VERSION 5.7 ;
  NOWIREEXTENSIONATPIN ON ;
  DIVIDERCHAR "/" ;
  BUSBITCHARS "[]" ;
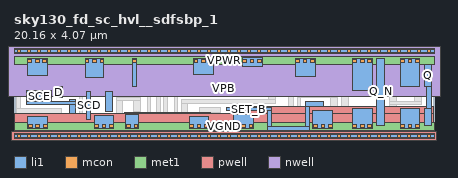
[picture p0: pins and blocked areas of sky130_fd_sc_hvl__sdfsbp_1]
MACRO sky130_fd_sc_hvl__sdfsbp_1
  CLASS BLOCK ;
  FOREIGN sky130_fd_sc_hvl__sdfsbp_1 ;
  ORIGIN 0.000 0.000 ;
  SIZE 20.160 BY 4.070 ;
  PIN CLK
    ANTENNAGATEAREA 0.585000 ;
    PORT
      LAYER li1 ;
        RECT 4.380 1.180 4.710 2.150 ;
    END
  END CLK
  PIN D
    ANTENNAGATEAREA 0.420000 ;
    PORT
      LAYER li1 ;
        RECT 1.975 1.845 2.305 2.355 ;
    END
  END D
  PIN SCD
    ANTENNAGATEAREA 0.420000 ;
    PORT
      LAYER li1 ;
        RECT 3.485 0.810 3.690 2.150 ;
    END
  END SCD
  PIN SCE
    ANTENNAGATEAREA 0.840000 ;
    PORT
      LAYER li1 ;
        RECT 0.605 1.665 1.795 2.165 ;
        RECT 2.680 1.665 2.955 1.765 ;
        RECT 0.605 1.495 2.955 1.665 ;
        RECT 2.680 1.095 2.955 1.495 ;
    END
  END SCE
  PIN SET_B
    ANTENNAGATEAREA 0.840000 ;
    PORT
      LAYER li1 ;
        RECT 14.000 1.425 14.845 1.645 ;
        RECT 10.205 1.210 12.355 1.380 ;
        RECT 12.185 0.435 12.355 1.210 ;
        RECT 14.000 0.435 14.170 1.425 ;
        RECT 12.185 0.265 14.170 0.435 ;
    END
  END SET_B
  PIN VGND
    USE GROUND ;
    PORT
      LAYER li1 ;
        RECT 0.665 0.365 1.615 0.915 ;
        RECT 3.870 0.365 4.760 0.995 ;
        RECT 5.370 0.365 5.960 1.020 ;
        RECT 8.410 0.365 9.360 0.960 ;
        RECT 10.545 0.365 11.495 1.030 ;
        RECT 14.350 0.365 15.300 1.245 ;
        RECT 16.240 0.365 17.190 1.325 ;
        RECT 18.535 0.365 19.485 1.325 ;
      LAYER mcon ;
        RECT 0.695 0.395 0.865 0.565 ;
        RECT 1.055 0.395 1.225 0.565 ;
        RECT 1.415 0.395 1.585 0.565 ;
        RECT 3.870 0.395 4.040 0.565 ;
        RECT 4.230 0.395 4.400 0.565 ;
        RECT 4.590 0.395 4.760 0.565 ;
        RECT 5.400 0.395 5.570 0.565 ;
        RECT 5.760 0.395 5.930 0.565 ;
        RECT 8.440 0.395 8.610 0.565 ;
        RECT 8.800 0.395 8.970 0.565 ;
        RECT 9.160 0.395 9.330 0.565 ;
        RECT 10.575 0.395 10.745 0.565 ;
        RECT 10.935 0.395 11.105 0.565 ;
        RECT 11.295 0.395 11.465 0.565 ;
        RECT 14.380 0.395 14.550 0.565 ;
        RECT 14.740 0.395 14.910 0.565 ;
        RECT 15.100 0.395 15.270 0.565 ;
        RECT 16.270 0.395 16.440 0.565 ;
        RECT 16.630 0.395 16.800 0.565 ;
        RECT 16.990 0.395 17.160 0.565 ;
        RECT 18.565 0.395 18.735 0.565 ;
        RECT 18.925 0.395 19.095 0.565 ;
        RECT 19.285 0.395 19.455 0.565 ;
      LAYER met1 ;
        RECT 0.000 0.255 20.160 0.625 ;
    END
  END VGND
  PIN VNB
    ANTENNADIFFAREA 3.427200 ;
    PORT
      LAYER pwell ;
        RECT 6.650 1.130 9.450 1.150 ;
        RECT 5.320 1.085 9.450 1.130 ;
        RECT 11.075 1.085 20.140 1.415 ;
        RECT 0.045 0.215 20.140 1.085 ;
        RECT -0.130 -0.215 20.290 0.215 ;
      LAYER li1 ;
        RECT 0.000 -0.085 20.160 0.085 ;
      LAYER mcon ;
        RECT 0.155 -0.085 0.325 0.085 ;
        RECT 0.635 -0.085 0.805 0.085 ;
        RECT 1.115 -0.085 1.285 0.085 ;
        RECT 1.595 -0.085 1.765 0.085 ;
        RECT 2.075 -0.085 2.245 0.085 ;
        RECT 2.555 -0.085 2.725 0.085 ;
        RECT 3.035 -0.085 3.205 0.085 ;
        RECT 3.515 -0.085 3.685 0.085 ;
        RECT 3.995 -0.085 4.165 0.085 ;
        RECT 4.475 -0.085 4.645 0.085 ;
        RECT 4.955 -0.085 5.125 0.085 ;
        RECT 5.435 -0.085 5.605 0.085 ;
        RECT 5.915 -0.085 6.085 0.085 ;
        RECT 6.395 -0.085 6.565 0.085 ;
        RECT 6.875 -0.085 7.045 0.085 ;
        RECT 7.355 -0.085 7.525 0.085 ;
        RECT 7.835 -0.085 8.005 0.085 ;
        RECT 8.315 -0.085 8.485 0.085 ;
        RECT 8.795 -0.085 8.965 0.085 ;
        RECT 9.275 -0.085 9.445 0.085 ;
        RECT 9.755 -0.085 9.925 0.085 ;
        RECT 10.235 -0.085 10.405 0.085 ;
        RECT 10.715 -0.085 10.885 0.085 ;
        RECT 11.195 -0.085 11.365 0.085 ;
        RECT 11.675 -0.085 11.845 0.085 ;
        RECT 12.155 -0.085 12.325 0.085 ;
        RECT 12.635 -0.085 12.805 0.085 ;
        RECT 13.115 -0.085 13.285 0.085 ;
        RECT 13.595 -0.085 13.765 0.085 ;
        RECT 14.075 -0.085 14.245 0.085 ;
        RECT 14.555 -0.085 14.725 0.085 ;
        RECT 15.035 -0.085 15.205 0.085 ;
        RECT 15.515 -0.085 15.685 0.085 ;
        RECT 15.995 -0.085 16.165 0.085 ;
        RECT 16.475 -0.085 16.645 0.085 ;
        RECT 16.955 -0.085 17.125 0.085 ;
        RECT 17.435 -0.085 17.605 0.085 ;
        RECT 17.915 -0.085 18.085 0.085 ;
        RECT 18.395 -0.085 18.565 0.085 ;
        RECT 18.875 -0.085 19.045 0.085 ;
        RECT 19.355 -0.085 19.525 0.085 ;
        RECT 19.835 -0.085 20.005 0.085 ;
      LAYER met1 ;
        RECT 0.000 -0.115 20.160 0.115 ;
    END
  END VNB
  PIN VPB
    ANTENNADIFFAREA 3.427200 ;
    PORT
      LAYER nwell ;
        RECT -0.330 1.885 20.490 4.485 ;
      LAYER li1 ;
        RECT 0.000 3.985 20.160 4.155 ;
      LAYER mcon ;
        RECT 0.155 3.985 0.325 4.155 ;
        RECT 0.635 3.985 0.805 4.155 ;
        RECT 1.115 3.985 1.285 4.155 ;
        RECT 1.595 3.985 1.765 4.155 ;
        RECT 2.075 3.985 2.245 4.155 ;
        RECT 2.555 3.985 2.725 4.155 ;
        RECT 3.035 3.985 3.205 4.155 ;
        RECT 3.515 3.985 3.685 4.155 ;
        RECT 3.995 3.985 4.165 4.155 ;
        RECT 4.475 3.985 4.645 4.155 ;
        RECT 4.955 3.985 5.125 4.155 ;
        RECT 5.435 3.985 5.605 4.155 ;
        RECT 5.915 3.985 6.085 4.155 ;
        RECT 6.395 3.985 6.565 4.155 ;
        RECT 6.875 3.985 7.045 4.155 ;
        RECT 7.355 3.985 7.525 4.155 ;
        RECT 7.835 3.985 8.005 4.155 ;
        RECT 8.315 3.985 8.485 4.155 ;
        RECT 8.795 3.985 8.965 4.155 ;
        RECT 9.275 3.985 9.445 4.155 ;
        RECT 9.755 3.985 9.925 4.155 ;
        RECT 10.235 3.985 10.405 4.155 ;
        RECT 10.715 3.985 10.885 4.155 ;
        RECT 11.195 3.985 11.365 4.155 ;
        RECT 11.675 3.985 11.845 4.155 ;
        RECT 12.155 3.985 12.325 4.155 ;
        RECT 12.635 3.985 12.805 4.155 ;
        RECT 13.115 3.985 13.285 4.155 ;
        RECT 13.595 3.985 13.765 4.155 ;
        RECT 14.075 3.985 14.245 4.155 ;
        RECT 14.555 3.985 14.725 4.155 ;
        RECT 15.035 3.985 15.205 4.155 ;
        RECT 15.515 3.985 15.685 4.155 ;
        RECT 15.995 3.985 16.165 4.155 ;
        RECT 16.475 3.985 16.645 4.155 ;
        RECT 16.955 3.985 17.125 4.155 ;
        RECT 17.435 3.985 17.605 4.155 ;
        RECT 17.915 3.985 18.085 4.155 ;
        RECT 18.395 3.985 18.565 4.155 ;
        RECT 18.875 3.985 19.045 4.155 ;
        RECT 19.355 3.985 19.525 4.155 ;
        RECT 19.835 3.985 20.005 4.155 ;
      LAYER met1 ;
        RECT 0.000 3.955 20.160 4.185 ;
    END
  END VPB
  PIN VPWR
    USE POWER ;
    PORT
      LAYER li1 ;
        RECT 0.640 2.885 1.590 3.705 ;
        RECT 3.415 2.805 4.305 3.705 ;
        RECT 5.695 2.400 5.865 3.705 ;
        RECT 8.615 2.960 9.565 3.705 ;
        RECT 10.955 3.350 11.905 3.755 ;
        RECT 13.500 2.875 14.450 3.705 ;
        RECT 16.240 2.195 17.190 3.735 ;
        RECT 18.535 2.355 19.485 3.705 ;
      LAYER mcon ;
        RECT 0.670 3.505 0.840 3.675 ;
        RECT 1.030 3.505 1.200 3.675 ;
        RECT 1.390 3.505 1.560 3.675 ;
        RECT 3.415 3.505 3.585 3.675 ;
        RECT 3.775 3.505 3.945 3.675 ;
        RECT 4.135 3.505 4.305 3.675 ;
        RECT 5.695 3.505 5.865 3.675 ;
        RECT 8.645 3.505 8.815 3.675 ;
        RECT 9.005 3.505 9.175 3.675 ;
        RECT 9.365 3.505 9.535 3.675 ;
        RECT 10.985 3.505 11.155 3.675 ;
        RECT 11.345 3.505 11.515 3.675 ;
        RECT 11.705 3.505 11.875 3.675 ;
        RECT 13.530 3.505 13.700 3.675 ;
        RECT 13.890 3.505 14.060 3.675 ;
        RECT 14.250 3.505 14.420 3.675 ;
        RECT 16.270 3.505 16.440 3.675 ;
        RECT 16.630 3.505 16.800 3.675 ;
        RECT 16.990 3.505 17.160 3.675 ;
        RECT 18.565 3.505 18.735 3.675 ;
        RECT 18.925 3.505 19.095 3.675 ;
        RECT 19.285 3.505 19.455 3.675 ;
      LAYER met1 ;
        RECT 0.000 3.445 20.160 3.815 ;
    END
  END VPWR
  PIN Q
    ANTENNADIFFAREA 0.498750 ;
    PORT
      LAYER li1 ;
        RECT 19.700 2.355 20.035 3.435 ;
        RECT 19.805 1.325 20.035 2.355 ;
        RECT 19.700 0.495 20.035 1.325 ;
    END
  END Q
  PIN Q_N
    ANTENNADIFFAREA 0.611250 ;
    PORT
      LAYER li1 ;
        RECT 17.405 0.495 17.785 3.735 ;
    END
  END Q_N
  OBS
      LAYER li1 ;
        RECT 4.485 3.635 5.515 3.805 ;
        RECT 0.130 2.705 0.460 3.305 ;
        RECT 2.400 3.055 2.730 3.305 ;
        RECT 2.400 2.885 3.235 3.055 ;
        RECT 0.130 2.535 2.885 2.705 ;
        RECT 0.130 1.315 0.300 2.535 ;
        RECT 2.635 2.015 2.885 2.535 ;
        RECT 3.065 2.625 3.235 2.885 ;
        RECT 4.485 2.625 4.655 3.635 ;
        RECT 4.835 2.805 5.165 3.455 ;
        RECT 3.065 2.455 4.655 2.625 ;
        RECT 0.130 1.095 2.300 1.315 ;
        RECT 0.130 0.495 0.485 1.095 ;
        RECT 3.135 0.915 3.305 2.455 ;
        RECT 2.425 0.745 3.305 0.915 ;
        RECT 4.940 1.870 5.165 2.805 ;
        RECT 5.345 2.220 5.515 3.635 ;
        RECT 6.045 3.390 7.295 3.560 ;
        RECT 6.045 2.220 6.215 3.390 ;
        RECT 5.345 2.050 6.215 2.220 ;
        RECT 6.395 2.290 6.645 3.210 ;
        RECT 6.840 2.740 7.295 3.390 ;
        RECT 4.940 1.700 6.065 1.870 ;
        RECT 2.425 0.495 2.755 0.745 ;
        RECT 4.940 0.515 5.190 1.700 ;
        RECT 5.735 1.200 6.065 1.700 ;
        RECT 6.395 1.020 6.565 2.290 ;
        RECT 6.840 1.060 7.010 2.740 ;
        RECT 6.190 0.435 6.565 1.020 ;
        RECT 6.760 0.615 7.010 1.060 ;
        RECT 7.190 2.290 7.520 2.560 ;
        RECT 7.190 0.435 7.360 2.290 ;
        RECT 7.700 2.080 7.995 3.240 ;
        RECT 9.745 3.170 10.775 3.340 ;
        RECT 9.745 2.780 9.915 3.170 ;
        RECT 10.605 3.000 12.335 3.170 ;
        RECT 8.200 2.610 9.915 2.780 ;
        RECT 8.200 2.290 8.530 2.610 ;
        RECT 10.095 2.430 10.425 2.990 ;
        RECT 8.910 2.260 10.425 2.430 ;
        RECT 11.315 2.080 11.645 2.555 ;
        RECT 12.025 2.295 12.335 3.000 ;
        RECT 12.515 2.695 12.845 3.755 ;
        RECT 14.970 2.695 15.300 3.175 ;
        RECT 12.515 2.525 15.300 2.695 ;
        RECT 12.025 2.125 13.405 2.295 ;
        RECT 7.700 1.910 11.645 2.080 ;
        RECT 7.700 1.060 7.870 1.910 ;
        RECT 12.200 1.730 12.530 1.875 ;
        RECT 7.540 0.640 7.870 1.060 ;
        RECT 8.050 1.560 12.530 1.730 ;
        RECT 8.050 1.150 8.325 1.560 ;
        RECT 13.165 1.415 13.405 2.125 ;
        RECT 13.585 1.995 13.755 2.525 ;
        RECT 15.685 2.345 16.060 2.675 ;
        RECT 13.935 2.175 16.060 2.345 ;
        RECT 13.585 1.825 15.545 1.995 ;
        RECT 8.050 0.435 8.220 1.150 ;
        RECT 8.910 1.140 9.910 1.380 ;
        RECT 9.580 0.515 9.910 1.140 ;
        RECT 12.655 0.785 12.985 1.325 ;
        RECT 13.585 0.785 13.755 1.825 ;
        RECT 15.215 1.425 15.545 1.825 ;
        RECT 15.730 0.825 16.060 2.175 ;
        RECT 18.025 1.675 18.355 3.185 ;
        RECT 19.245 1.675 19.575 2.175 ;
        RECT 18.025 1.505 19.575 1.675 ;
        RECT 18.025 0.825 18.355 1.505 ;
        RECT 12.655 0.615 13.755 0.785 ;
        RECT 6.190 0.265 8.220 0.435 ;
  END
END sky130_fd_sc_hvl__sdfsbp_1
END LIBRARY

